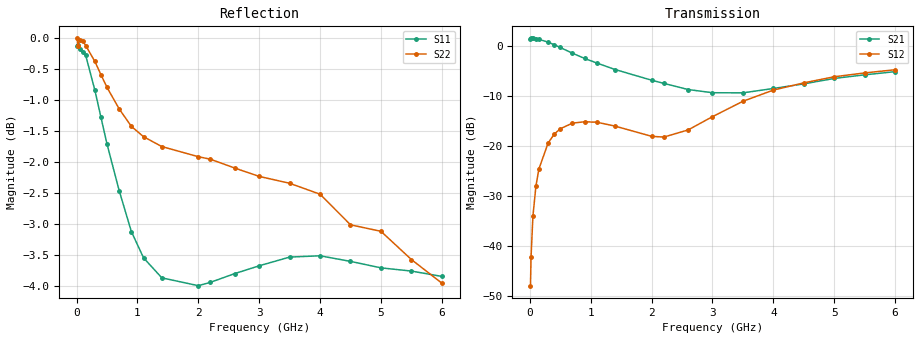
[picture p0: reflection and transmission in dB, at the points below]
! Infineon Technologies  Discrete & RF Semiconductors
! BFS17W
! Si NPN RF Bipolar Junction Transistor in SOT323
! VCE = 4 V  IC = 0.3 mA
! Common Emitter S-Parameters:  August  1999
# GHz  S  MA  R  50
!  f  S11  S21  S12  S22
! GHz  MAG  ANG  MAG  ANG  MAG  ANG  MAG  ANG
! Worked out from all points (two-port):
!   36 points, 10 MHz to 6 GHz, reference 50 ohm
!   highest |S21| = 1.53 dB at 50 MHz (marker M1); lowest = -9.4 dB at 3.5 GHz (marker M2)
!   |S21| within 3 dB of the highest: start of sweep to 705.1 MHz
!   lowest |S11| = -4.0 dB at 2 GHz (marker M3), VSWR 4.42, Z = 11.3 + j2.74 ohm
!   |S11| at or under -10 dB: nowhere
!   |S22| runs from -4.0 to 0.0 dB; largest |S21 - S12| = 1.2
!   S11 on the Smith chart (normalised r, x): 10 MHz: 29, -57; 300 MHz: 0.28, -2.16; 700 MHz: 0.24, -0.81; 1.4 GHz: 0.23, -0.21; 3 GHz: 0.24, +0.38; 6 GHz: 0.52, +1.10
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0.01  0.9862 -1.6  1.189 179.4  0.004 87.8  0.9999 0.0
0.02  0.9881 -3.6  1.19 177.3  0.0078 85.5  0.9851 -0.8
0.05  0.9803 -8.4  1.193 172.7  0.0198 85.8  0.9976 -2.4
0.1  0.9748 -16.6  1.182 165.9  0.0399 80.0  0.9952 -4.8
0.15  0.9687 -25.8  1.167 158.4  0.0592 74.3  0.9867 -7.0
0.3  0.9082 -49.1  1.093 138.3  0.107 60.1  0.958 -13.3
0.4  0.8636 -63.5  1.03 125.9  0.1312 52.0  0.9347 -17.0
0.5  0.8214 -76.8  0.967 115.2  0.1488 44.9  0.9127 -20.1
0.7  0.7532 -100.0  0.847 96.6  0.1692 34.0  0.8769 -25.8
0.9  0.698 -119.3  0.751 81.9  0.1747 26.1  0.8489 -31.2
1.1  0.6647 -135.6  0.676 69.4  0.1729 20.6  0.8327 -36.3
1.4  0.6404 -155.4  0.582 55.5  0.158 16.8  0.8176 -44.3
2  0.6311 173.4  0.455 37.4  0.1249 28.1  0.8023 -61.7
2.2  0.6351 165.3  0.423 34.1  0.1227 37.5  0.7985 -67.7
2.6  0.6455 149.8  0.367 31.0  0.1447 56.1  0.7855 -80.2
3  0.6549 136.1  0.341 32.9  0.1965 65.1  0.7734 -92.3
3.5  0.6656 121.2  0.34 37.5  0.2799 65.3  0.7636 -108.1
4  0.6672 108.8  0.376 40.1  0.3625 59.5  0.7482 -124.8
4.5  0.6603 98.1  0.418 39.3  0.4279 52.2  0.7068 -140.4
5  0.6524 90.0  0.474 36.1  0.4926 45.0  0.6983 -154.1
5.5  0.6485 83.2  0.515 31.8  0.538 37.9  0.6626 -168.1
6  0.6421 77.8  0.554 26.9  0.5792 31.4  0.6341 179.8
